###############################################################
#  Generated by:      Cadence Innovus 21.10-p004_1
#  OS:                Linux x86_64(Host ID caen-vnc-mi07.engin.umich.edu)
#  Generated on:      Fri Mar 18 23:40:56 2022
#  Design:            mult_block
#  Command:           write_lef_abstract /afs/umich.edu/class/eecs627/w23/template_prj/mult_block/apr/data/mult_block.lef -specifyTopLayer 4 -stripePin -PGpinLayers 4
###############################################################

VERSION 5.8 ;

BUSBITCHARS "[]" ;
DIVIDERCHAR "/" ;

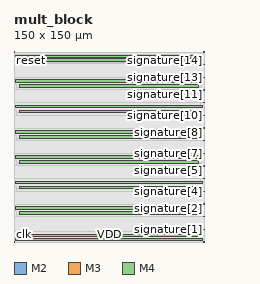
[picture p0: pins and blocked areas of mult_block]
MACRO mult_block
  CLASS BLOCK ;
  SIZE 150.000000 BY 150.000000 ;
  FOREIGN mult_block 0.000000 0.000000 ;
  ORIGIN 0 0 ;
  SYMMETRY X Y R90 ;
  PIN clk
    DIRECTION INPUT ;
    USE SIGNAL ;
    ANTENNAPARTIALMETALAREA 0.16 LAYER M2  ;
    ANTENNAPARTIALMETALSIDEAREA 0.0016 LAYER M2  ;
    ANTENNAPARTIALCUTAREA 0.08 LAYER V2  ;
    ANTENNAPARTIALMETALAREA 0.2 LAYER M3  ;
    ANTENNAPARTIALMETALSIDEAREA 0.0024 LAYER M3  ;
    ANTENNAPARTIALCUTAREA 0.08 LAYER V3  ;
    ANTENNAPARTIALMETALAREA 4.36 LAYER M4  ;
    ANTENNAPARTIALMETALSIDEAREA 0.044 LAYER M4  ;
    ANTENNAMODEL OXIDE1 ;
    ANTENNAGATEAREA 0.8352 LAYER M4  ;
    ANTENNAMAXAREACAR 6.74138 LAYER M4  ;
    ANTENNAMAXSIDEAREACAR 0.0687021 LAYER M4  ;
    ANTENNAMAXCUTCAR 0.287356 LAYER V4  ;
    PORT
      LAYER M2 ;
        RECT 0.000000 -0.100000 0.600000 0.100000 ;
    END
  END clk
  PIN reset
    DIRECTION INPUT ;
    USE SIGNAL ;
    ANTENNAPARTIALMETALAREA 0.4 LAYER M2  ;
    ANTENNAPARTIALMETALSIDEAREA 0.004 LAYER M2  ;
    ANTENNAPARTIALCUTAREA 0.08 LAYER V2  ;
    ANTENNAPARTIALMETALAREA 10.2 LAYER M3  ;
    ANTENNAPARTIALMETALSIDEAREA 0.1024 LAYER M3  ;
    ANTENNAMODEL OXIDE1 ;
    ANTENNAGATEAREA 0.4176 LAYER M3  ;
    ANTENNAMAXAREACAR 30.1466 LAYER M3  ;
    ANTENNAMAXSIDEAREACAR 0.303975 LAYER M3  ;
    ANTENNAMAXCUTCAR 0.287356 LAYER V3  ;
    PORT
      LAYER M2 ;
        RECT 0.000000 149.900000 0.600000 150.100000 ;
    END
  END reset
  PIN signature[15]
    DIRECTION OUTPUT ;
    USE SIGNAL ;
    ANTENNAPARTIALMETALAREA 0.08 LAYER M3  ;
    ANTENNAPARTIALMETALSIDEAREA 0.0008 LAYER M3  ;
    ANTENNAPARTIALCUTAREA 0.04 LAYER V3  ;
    ANTENNADIFFAREA 3.046 LAYER M4  ;
    ANTENNAPARTIALMETALAREA 5 LAYER M4  ;
    ANTENNAPARTIALMETALSIDEAREA 0.0504 LAYER M4  ;
    ANTENNAMODEL OXIDE1 ;
    ANTENNAGATEAREA 0.5928 LAYER M4  ;
    ANTENNAMAXAREACAR 145.654 LAYER M4  ;
    ANTENNAMAXSIDEAREACAR 1.46274 LAYER M4  ;
    ANTENNAMAXCUTCAR 1.45637 LAYER V4  ;
    PORT
      LAYER M3 ;
        RECT 149.400000 149.900000 150.000000 150.100000 ;
    END
  END signature[15]
  PIN signature[14]
    DIRECTION OUTPUT ;
    USE SIGNAL ;
    ANTENNADIFFAREA 3.046 LAYER M3  ;
    ANTENNAPARTIALMETALAREA 2.76 LAYER M3  ;
    ANTENNAPARTIALMETALSIDEAREA 0.028 LAYER M3  ;
    ANTENNAMODEL OXIDE1 ;
    ANTENNAGATEAREA 0.2184 LAYER M3  ;
    ANTENNAMAXAREACAR 13.8901 LAYER M3  ;
    ANTENNAMAXSIDEAREACAR 0.142857 LAYER M3  ;
    ANTENNAMAXCUTCAR 0.549451 LAYER V3  ;
    PORT
      LAYER M3 ;
        RECT 149.400000 139.900000 150.000000 140.100000 ;
    END
  END signature[14]
  PIN signature[13]
    DIRECTION OUTPUT ;
    USE SIGNAL ;
    ANTENNAPARTIALMETALAREA 0.16 LAYER M3  ;
    ANTENNAPARTIALMETALSIDEAREA 0.0016 LAYER M3  ;
    ANTENNAPARTIALCUTAREA 0.08 LAYER V3  ;
    ANTENNADIFFAREA 3.046 LAYER M4  ;
    ANTENNAPARTIALMETALAREA 1.4 LAYER M4  ;
    ANTENNAPARTIALMETALSIDEAREA 0.0144 LAYER M4  ;
    ANTENNAMODEL OXIDE1 ;
    ANTENNAGATEAREA 0.2184 LAYER M4  ;
    ANTENNAMAXAREACAR 22.315 LAYER M4  ;
    ANTENNAMAXSIDEAREACAR 0.230769 LAYER M4  ;
    ANTENNAMAXCUTCAR 1.28205 LAYER V4  ;
    PORT
      LAYER M3 ;
        RECT 149.400000 129.900000 150.000000 130.100000 ;
    END
  END signature[13]
  PIN signature[12]
    DIRECTION OUTPUT ;
    USE SIGNAL ;
    ANTENNADIFFAREA 2.603 LAYER M3  ;
    ANTENNAPARTIALMETALAREA 1.48 LAYER M3  ;
    ANTENNAPARTIALMETALSIDEAREA 0.0152 LAYER M3  ;
    ANTENNAMODEL OXIDE1 ;
    ANTENNAGATEAREA 0.2184 LAYER M3  ;
    ANTENNAMAXAREACAR 8.0293 LAYER M3  ;
    ANTENNAMAXSIDEAREACAR 0.0842491 LAYER M3  ;
    ANTENNAMAXCUTCAR 0.549451 LAYER V3  ;
    PORT
      LAYER M3 ;
        RECT 149.400000 119.900000 150.000000 120.100000 ;
    END
  END signature[12]
  PIN signature[11]
    DIRECTION OUTPUT ;
    USE SIGNAL ;
    ANTENNADIFFAREA 3.046 LAYER M3  ;
    ANTENNAPARTIALMETALAREA 1.56 LAYER M3  ;
    ANTENNAPARTIALMETALSIDEAREA 0.016 LAYER M3  ;
    ANTENNAMODEL OXIDE1 ;
    ANTENNAGATEAREA 0.2184 LAYER M3  ;
    ANTENNAMAXAREACAR 13.5238 LAYER M3  ;
    ANTENNAMAXSIDEAREACAR 0.139194 LAYER M3  ;
    ANTENNAMAXCUTCAR 0.549451 LAYER V3  ;
    PORT
      LAYER M3 ;
        RECT 149.400000 109.900000 150.000000 110.100000 ;
    END
  END signature[11]
  PIN signature[10]
    DIRECTION OUTPUT ;
    USE SIGNAL ;
    ANTENNADIFFAREA 1.76 LAYER M3  ;
    ANTENNAPARTIALMETALAREA 0.68 LAYER M3  ;
    ANTENNAPARTIALMETALSIDEAREA 0.0072 LAYER M3  ;
    PORT
      LAYER M3 ;
        RECT 149.400000 99.900000 150.000000 100.100000 ;
    END
  END signature[10]
  PIN signature[9]
    DIRECTION OUTPUT ;
    USE SIGNAL ;
    ANTENNAPARTIALMETALAREA 0.16 LAYER M3  ;
    ANTENNAPARTIALMETALSIDEAREA 0.0016 LAYER M3  ;
    ANTENNAPARTIALCUTAREA 0.08 LAYER V3  ;
    ANTENNADIFFAREA 3.046 LAYER M4  ;
    ANTENNAPARTIALMETALAREA 1.4 LAYER M4  ;
    ANTENNAPARTIALMETALSIDEAREA 0.0144 LAYER M4  ;
    ANTENNAMODEL OXIDE1 ;
    ANTENNAGATEAREA 0.4368 LAYER M4  ;
    ANTENNAMAXAREACAR 13.2491 LAYER M4  ;
    ANTENNAMAXSIDEAREACAR 0.135531 LAYER M4  ;
    ANTENNAMAXCUTCAR 0.549451 LAYER V4  ;
    PORT
      LAYER M3 ;
        RECT 149.400000 89.900000 150.000000 90.100000 ;
    END
  END signature[9]
  PIN signature[8]
    DIRECTION OUTPUT ;
    USE SIGNAL ;
    ANTENNAPARTIALMETALAREA 0.16 LAYER M3  ;
    ANTENNAPARTIALMETALSIDEAREA 0.0016 LAYER M3  ;
    ANTENNAPARTIALCUTAREA 0.08 LAYER V3  ;
    ANTENNADIFFAREA 3.046 LAYER M4  ;
    ANTENNAPARTIALMETALAREA 1.4 LAYER M4  ;
    ANTENNAPARTIALMETALSIDEAREA 0.0144 LAYER M4  ;
    ANTENNAMODEL OXIDE1 ;
    ANTENNAGATEAREA 0.2184 LAYER M4  ;
    ANTENNAMAXAREACAR 12.7912 LAYER M4  ;
    ANTENNAMAXSIDEAREACAR 0.135531 LAYER M4  ;
    ANTENNAMAXCUTCAR 0.915751 LAYER V4  ;
    PORT
      LAYER M3 ;
        RECT 149.400000 79.900000 150.000000 80.100000 ;
    END
  END signature[8]
  PIN signature[7]
    DIRECTION OUTPUT ;
    USE SIGNAL ;
    ANTENNAPARTIALMETALAREA 0.16 LAYER M3  ;
    ANTENNAPARTIALMETALSIDEAREA 0.0016 LAYER M3  ;
    ANTENNAPARTIALCUTAREA 0.08 LAYER V3  ;
    ANTENNADIFFAREA 3.046 LAYER M4  ;
    ANTENNAPARTIALMETALAREA 1.4 LAYER M4  ;
    ANTENNAPARTIALMETALSIDEAREA 0.0144 LAYER M4  ;
    ANTENNAMODEL OXIDE1 ;
    ANTENNAGATEAREA 0.2184 LAYER M4  ;
    ANTENNAMAXAREACAR 12.7912 LAYER M4  ;
    ANTENNAMAXSIDEAREACAR 0.135531 LAYER M4  ;
    ANTENNAMAXCUTCAR 0.915751 LAYER V4  ;
    PORT
      LAYER M3 ;
        RECT 149.400000 69.900000 150.000000 70.100000 ;
    END
  END signature[7]
  PIN signature[6]
    DIRECTION OUTPUT ;
    USE SIGNAL ;
    ANTENNADIFFAREA 3.046 LAYER M3  ;
    ANTENNAPARTIALMETALAREA 1.92 LAYER M3  ;
    ANTENNAPARTIALMETALSIDEAREA 0.02 LAYER M3  ;
    ANTENNAMODEL OXIDE1 ;
    ANTENNAGATEAREA 0.2184 LAYER M3  ;
    ANTENNAMAXAREACAR 10.7766 LAYER M3  ;
    ANTENNAMAXSIDEAREACAR 0.113553 LAYER M3  ;
    ANTENNAMAXCUTCAR 0.549451 LAYER V3  ;
    PORT
      LAYER M3 ;
        RECT 149.400000 59.900000 150.000000 60.100000 ;
    END
  END signature[6]
  PIN signature[5]
    DIRECTION OUTPUT ;
    USE SIGNAL ;
    ANTENNAPARTIALMETALAREA 0.16 LAYER M3  ;
    ANTENNAPARTIALMETALSIDEAREA 0.0016 LAYER M3  ;
    ANTENNAPARTIALCUTAREA 0.08 LAYER V3  ;
    ANTENNADIFFAREA 3.046 LAYER M4  ;
    ANTENNAPARTIALMETALAREA 1.4 LAYER M4  ;
    ANTENNAPARTIALMETALSIDEAREA 0.0144 LAYER M4  ;
    ANTENNAMODEL OXIDE1 ;
    ANTENNAGATEAREA 0.2184 LAYER M4  ;
    ANTENNAMAXAREACAR 14.4396 LAYER M4  ;
    ANTENNAMAXSIDEAREACAR 0.150183 LAYER M4  ;
    ANTENNAMAXCUTCAR 0.915751 LAYER V4  ;
    PORT
      LAYER M3 ;
        RECT 149.400000 49.900000 150.000000 50.100000 ;
    END
  END signature[5]
  PIN signature[4]
    DIRECTION OUTPUT ;
    USE SIGNAL ;
    ANTENNAPARTIALMETALAREA 0.16 LAYER M3  ;
    ANTENNAPARTIALMETALSIDEAREA 0.0016 LAYER M3  ;
    ANTENNAPARTIALCUTAREA 0.08 LAYER V3  ;
    ANTENNADIFFAREA 3.046 LAYER M4  ;
    ANTENNAPARTIALMETALAREA 1.48 LAYER M4  ;
    ANTENNAPARTIALMETALSIDEAREA 0.0152 LAYER M4  ;
    ANTENNAMODEL OXIDE1 ;
    ANTENNAGATEAREA 0.2184 LAYER M4  ;
    ANTENNAMAXAREACAR 14.8059 LAYER M4  ;
    ANTENNAMAXSIDEAREACAR 0.153846 LAYER M4  ;
    ANTENNAMAXCUTCAR 0.915751 LAYER V4  ;
    PORT
      LAYER M3 ;
        RECT 149.400000 39.900000 150.000000 40.100000 ;
    END
  END signature[4]
  PIN signature[3]
    DIRECTION OUTPUT ;
    USE SIGNAL ;
    ANTENNADIFFAREA 3.046 LAYER M3  ;
    ANTENNAPARTIALMETALAREA 0.84 LAYER M3  ;
    ANTENNAPARTIALMETALSIDEAREA 0.0088 LAYER M3  ;
    ANTENNAMODEL OXIDE1 ;
    ANTENNAGATEAREA 0.2184 LAYER M3  ;
    ANTENNAMAXAREACAR 9.86081 LAYER M3  ;
    ANTENNAMAXSIDEAREACAR 0.102564 LAYER M3  ;
    ANTENNAMAXCUTCAR 0.549451 LAYER V3  ;
    PORT
      LAYER M3 ;
        RECT 149.400000 29.900000 150.000000 30.100000 ;
    END
  END signature[3]
  PIN signature[2]
    DIRECTION OUTPUT ;
    USE SIGNAL ;
    ANTENNADIFFAREA 3.046 LAYER M3  ;
    ANTENNAPARTIALMETALAREA 1.2 LAYER M3  ;
    ANTENNAPARTIALMETALSIDEAREA 0.0128 LAYER M3  ;
    ANTENNAMODEL OXIDE1 ;
    ANTENNAGATEAREA 0.2184 LAYER M3  ;
    ANTENNAMAXAREACAR 6.74725 LAYER M3  ;
    ANTENNAMAXSIDEAREACAR 0.0732601 LAYER M3  ;
    ANTENNAMAXCUTCAR 0.549451 LAYER V3  ;
    PORT
      LAYER M3 ;
        RECT 149.400000 19.900000 150.000000 20.100000 ;
    END
  END signature[2]
  PIN signature[1]
    DIRECTION OUTPUT ;
    USE SIGNAL ;
    ANTENNADIFFAREA 3.046 LAYER M3  ;
    ANTENNAPARTIALMETALAREA 2.44 LAYER M3  ;
    ANTENNAPARTIALMETALSIDEAREA 0.0248 LAYER M3  ;
    ANTENNAMODEL OXIDE1 ;
    ANTENNAGATEAREA 0.2184 LAYER M3  ;
    ANTENNAMAXAREACAR 19.3846 LAYER M3  ;
    ANTENNAMAXSIDEAREACAR 0.197802 LAYER M3  ;
    ANTENNAMAXCUTCAR 0.549451 LAYER V3  ;
    PORT
      LAYER M3 ;
        RECT 149.400000 9.900000 150.000000 10.100000 ;
    END
  END signature[1]
  PIN signature[0]
    DIRECTION OUTPUT ;
    USE SIGNAL ;
    ANTENNAPARTIALMETALAREA 0.16 LAYER M3  ;
    ANTENNAPARTIALMETALSIDEAREA 0.0016 LAYER M3  ;
    ANTENNAPARTIALCUTAREA 0.08 LAYER V3  ;
    ANTENNADIFFAREA 3.046 LAYER M4  ;
    ANTENNAPARTIALMETALAREA 3.8 LAYER M4  ;
    ANTENNAPARTIALMETALSIDEAREA 0.0384 LAYER M4  ;
    ANTENNAMODEL OXIDE1 ;
    ANTENNAGATEAREA 0.2184 LAYER M4  ;
    ANTENNAMAXAREACAR 24.696 LAYER M4  ;
    ANTENNAMAXSIDEAREACAR 0.252747 LAYER M4  ;
    ANTENNAMAXCUTCAR 0.915751 LAYER V4  ;
    PORT
      LAYER M3 ;
        RECT 149.400000 -0.100000 150.000000 0.100000 ;
    END
  END signature[0]
  PIN VSS
    DIRECTION INOUT ;
    USE GROUND ;

# P/G power stripe data as pin
    PORT
      LAYER M4 ;
        RECT 1.000000 1.000000 149.000000 3.000000 ;
        RECT 1.000000 26.000000 149.000000 28.000000 ;
        RECT 1.000000 46.000000 149.000000 48.000000 ;
        RECT 1.000000 66.000000 149.000000 68.000000 ;
        RECT 1.000000 86.000000 149.000000 88.000000 ;
        RECT 1.000000 106.000000 149.000000 108.000000 ;
        RECT 1.000000 145.600000 149.000000 147.600000 ;
        RECT 1.000000 126.000000 149.000000 128.000000 ;
    END
# end of P/G power stripe data as pin

  END VSS
  PIN VDD
    DIRECTION INOUT ;
    USE POWER ;

# P/G power stripe data as pin
    PORT
      LAYER M4 ;
        RECT 4.000000 4.000000 146.000000 6.000000 ;
        RECT 4.000000 22.000000 146.000000 24.000000 ;
        RECT 4.000000 42.000000 146.000000 44.000000 ;
        RECT 4.000000 62.000000 146.000000 64.000000 ;
        RECT 4.000000 82.000000 146.000000 84.000000 ;
        RECT 4.000000 102.000000 146.000000 104.000000 ;
        RECT 4.000000 142.600000 146.000000 144.600000 ;
        RECT 4.000000 122.000000 146.000000 124.000000 ;
    END
# end of P/G power stripe data as pin

  END VDD
  OBS
    LAYER M1 ;
      RECT 0.000000 0.000000 150.000000 150.000000 ;
    LAYER M2 ;
      RECT 2.520000 147.980000 150.000000 150.000000 ;
      RECT 0.000000 2.020000 150.000000 147.980000 ;
      RECT 2.520000 0.000000 150.000000 2.020000 ;
    LAYER M3 ;
      RECT 0.000000 147.980000 147.480000 150.000000 ;
      RECT 0.000000 142.020000 150.000000 147.980000 ;
      RECT 0.000000 137.980000 147.480000 142.020000 ;
      RECT 0.000000 132.020000 150.000000 137.980000 ;
      RECT 0.000000 127.980000 147.480000 132.020000 ;
      RECT 0.000000 122.020000 150.000000 127.980000 ;
      RECT 0.000000 117.980000 147.480000 122.020000 ;
      RECT 0.000000 112.020000 150.000000 117.980000 ;
      RECT 0.000000 107.980000 147.480000 112.020000 ;
      RECT 0.000000 102.020000 150.000000 107.980000 ;
      RECT 0.000000 97.980000 147.480000 102.020000 ;
      RECT 0.000000 92.020000 150.000000 97.980000 ;
      RECT 0.000000 87.980000 147.480000 92.020000 ;
      RECT 0.000000 82.020000 150.000000 87.980000 ;
      RECT 0.000000 77.980000 147.480000 82.020000 ;
      RECT 0.000000 72.020000 150.000000 77.980000 ;
      RECT 0.000000 67.980000 147.480000 72.020000 ;
      RECT 0.000000 62.020000 150.000000 67.980000 ;
      RECT 0.000000 57.980000 147.480000 62.020000 ;
      RECT 0.000000 52.020000 150.000000 57.980000 ;
      RECT 0.000000 47.980000 147.480000 52.020000 ;
      RECT 0.000000 42.020000 150.000000 47.980000 ;
      RECT 0.000000 37.980000 147.480000 42.020000 ;
      RECT 0.000000 32.020000 150.000000 37.980000 ;
      RECT 0.000000 27.980000 147.480000 32.020000 ;
      RECT 0.000000 22.020000 150.000000 27.980000 ;
      RECT 0.000000 17.980000 147.480000 22.020000 ;
      RECT 0.000000 12.020000 150.000000 17.980000 ;
      RECT 0.000000 7.980000 147.480000 12.020000 ;
      RECT 0.000000 2.020000 150.000000 7.980000 ;
      RECT 0.000000 0.000000 147.480000 2.020000 ;
    LAYER M4 ;
      RECT 0.000000 149.520000 150.000000 150.000000 ;
      RECT 147.920000 140.680000 150.000000 143.680000 ;
      RECT 0.000000 140.680000 2.080000 143.680000 ;
      RECT 0.000000 129.920000 150.000000 140.680000 ;
      RECT 147.920000 120.080000 150.000000 124.080000 ;
      RECT 0.000000 120.080000 2.080000 124.080000 ;
      RECT 0.000000 109.920000 150.000000 120.080000 ;
      RECT 147.920000 100.080000 150.000000 104.080000 ;
      RECT 0.000000 100.080000 2.080000 104.080000 ;
      RECT 0.000000 89.920000 150.000000 100.080000 ;
      RECT 147.920000 80.080000 150.000000 84.080000 ;
      RECT 0.000000 80.080000 2.080000 84.080000 ;
      RECT 0.000000 69.920000 150.000000 80.080000 ;
      RECT 147.920000 60.080000 150.000000 64.080000 ;
      RECT 0.000000 60.080000 2.080000 64.080000 ;
      RECT 0.000000 49.920000 150.000000 60.080000 ;
      RECT 147.920000 40.080000 150.000000 44.080000 ;
      RECT 0.000000 40.080000 2.080000 44.080000 ;
      RECT 0.000000 29.920000 150.000000 40.080000 ;
      RECT 147.920000 20.080000 150.000000 24.080000 ;
      RECT 0.000000 20.080000 2.080000 24.080000 ;
      RECT 0.000000 7.920000 150.000000 20.080000 ;
      RECT 147.920000 4.920000 150.000000 7.920000 ;
      RECT 0.000000 4.920000 2.080000 7.920000 ;
  END
END mult_block

END LIBRARY
